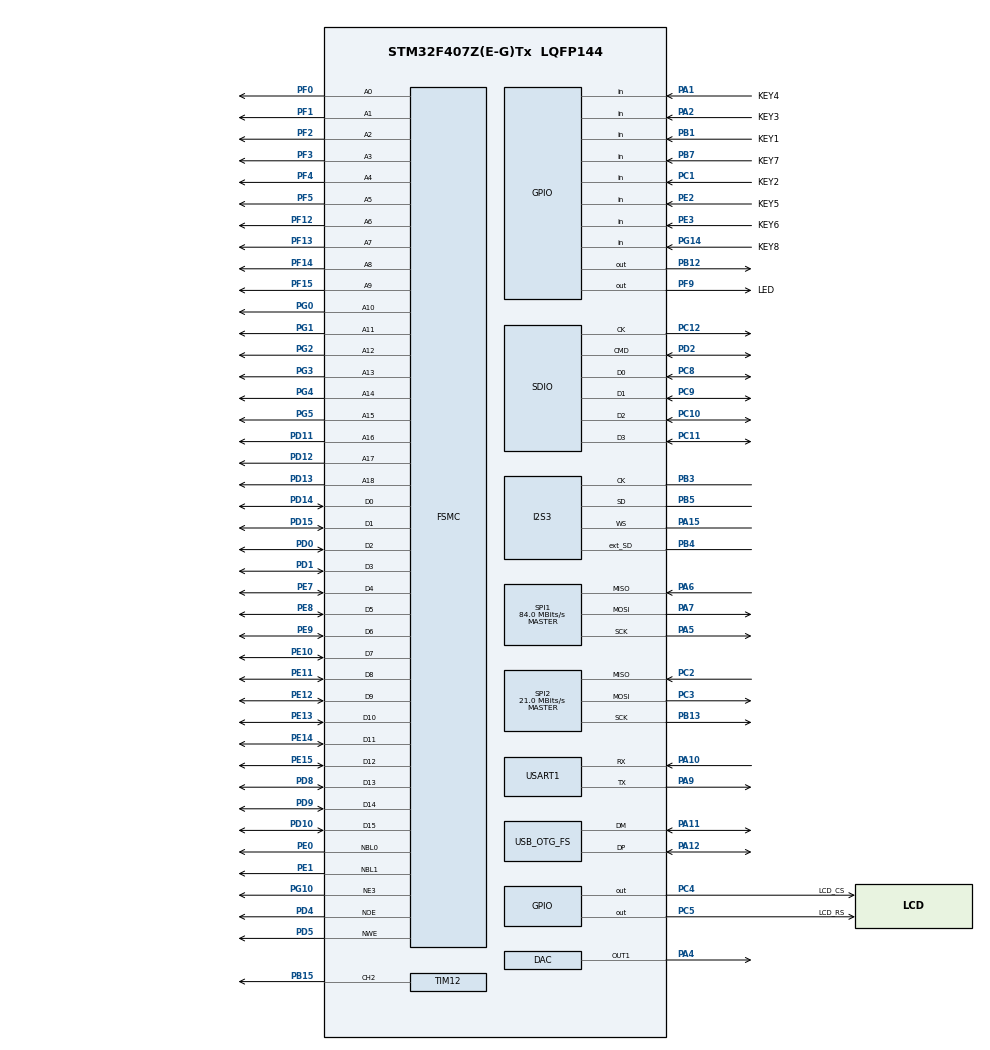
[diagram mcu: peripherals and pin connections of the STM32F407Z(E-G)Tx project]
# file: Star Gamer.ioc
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Dma.Request0=SDIO_RX
Dma.Request1=SDIO_TX
Dma.Request2=SPI2_TX
Dma.Request3=SPI1_TX
Dma.Request4=SPI1_RX
Dma.Request5=SPI3_TX
Dma.SDIO_RX.0.Direction=DMA_PERIPH_TO_MEMORY
Dma.SDIO_RX.0.FIFOMode=DMA_FIFOMODE_ENABLE
Dma.SDIO_RX.0.FIFOThreshold=DMA_FIFO_THRESHOLD_FULL
Dma.SDIO_RX.0.Instance=DMA2_Stream3
Dma.SDIO_RX.0.MemBurst=DMA_MBURST_INC4
Dma.SDIO_RX.0.MemDataAlignment=DMA_MDATAALIGN_WORD
Dma.SDIO_RX.0.MemInc=DMA_MINC_ENABLE
Dma.SDIO_RX.0.Mode=DMA_PFCTRL
Dma.SDIO_RX.0.PeriphBurst=DMA_PBURST_INC4
Dma.SDIO_RX.0.PeriphDataAlignment=DMA_PDATAALIGN_WORD
Dma.SDIO_RX.0.PeriphInc=DMA_PINC_DISABLE
Dma.SDIO_RX.0.Priority=DMA_PRIORITY_VERY_HIGH
Dma.SDIO_TX.1.Direction=DMA_MEMORY_TO_PERIPH
Dma.SDIO_TX.1.FIFOMode=DMA_FIFOMODE_ENABLE
Dma.SDIO_TX.1.FIFOThreshold=DMA_FIFO_THRESHOLD_FULL
Dma.SDIO_TX.1.Instance=DMA2_Stream6
Dma.SDIO_TX.1.MemBurst=DMA_MBURST_INC4
Dma.SDIO_TX.1.MemDataAlignment=DMA_MDATAALIGN_WORD
Dma.SDIO_TX.1.MemInc=DMA_MINC_ENABLE
Dma.SDIO_TX.1.Mode=DMA_PFCTRL
Dma.SDIO_TX.1.PeriphBurst=DMA_PBURST_INC4
Dma.SDIO_TX.1.PeriphDataAlignment=DMA_PDATAALIGN_WORD
Dma.SDIO_TX.1.PeriphInc=DMA_PINC_DISABLE
Dma.SDIO_TX.1.Priority=DMA_PRIORITY_VERY_HIGH
Dma.SPI1_RX.4.Direction=DMA_PERIPH_TO_MEMORY
Dma.SPI1_RX.4.FIFOMode=DMA_FIFOMODE_DISABLE
Dma.SPI1_RX.4.Instance=DMA2_Stream0
Dma.SPI1_RX.4.MemDataAlignment=DMA_MDATAALIGN_BYTE
Dma.SPI1_RX.4.MemInc=DMA_MINC_ENABLE
Dma.SPI1_RX.4.Mode=DMA_NORMAL
Dma.SPI1_RX.4.PeriphDataAlignment=DMA_PDATAALIGN_BYTE
Dma.SPI1_RX.4.PeriphInc=DMA_PINC_DISABLE
Dma.SPI1_RX.4.Priority=DMA_PRIORITY_MEDIUM
Dma.SPI1_TX.3.Direction=DMA_MEMORY_TO_PERIPH
Dma.SPI1_TX.3.FIFOMode=DMA_FIFOMODE_DISABLE
Dma.SPI1_TX.3.Instance=DMA2_Stream5
Dma.SPI1_TX.3.MemDataAlignment=DMA_MDATAALIGN_BYTE
Dma.SPI1_TX.3.MemInc=DMA_MINC_ENABLE
Dma.SPI1_TX.3.Mode=DMA_NORMAL
Dma.SPI1_TX.3.PeriphDataAlignment=DMA_PDATAALIGN_BYTE
Dma.SPI1_TX.3.PeriphInc=DMA_PINC_DISABLE
Dma.SPI1_TX.3.Priority=DMA_PRIORITY_MEDIUM
Dma.SPI2_TX.2.Direction=DMA_MEMORY_TO_PERIPH
Dma.SPI2_TX.2.FIFOMode=DMA_FIFOMODE_DISABLE
Dma.SPI2_TX.2.Instance=DMA1_Stream4
Dma.SPI2_TX.2.MemDataAlignment=DMA_MDATAALIGN_BYTE
Dma.SPI2_TX.2.MemInc=DMA_MINC_ENABLE
Dma.SPI2_TX.2.Mode=DMA_NORMAL
Dma.SPI2_TX.2.PeriphDataAlignment=DMA_PDATAALIGN_BYTE
Dma.SPI2_TX.2.PeriphInc=DMA_PINC_DISABLE
Dma.SPI2_TX.2.Priority=DMA_PRIORITY_LOW
Dma.SPI3_TX.5.Direction=DMA_MEMORY_TO_PERIPH
Dma.SPI3_TX.5.FIFOMode=DMA_FIFOMODE_DISABLE
Dma.SPI3_TX.5.Instance=DMA1_Stream7
Dma.SPI3_TX.5.MemDataAlignment=DMA_MDATAALIGN_HALFWORD
Dma.SPI3_TX.5.MemInc=DMA_MINC_ENABLE
Dma.SPI3_TX.5.Mode=DMA_CIRCULAR
Dma.SPI3_TX.5.PeriphDataAlignment=DMA_PDATAALIGN_HALFWORD
Dma.SPI3_TX.5.PeriphInc=DMA_PINC_DISABLE
Dma.SPI3_TX.5.Priority=DMA_PRIORITY_HIGH
FATFS._CODE_PAGE=936
FATFS._USE_LFN=3
FATFS._USE_MUTEX=1
FREERTOS.INCLUDE_xEventGroupSetBitFromISR=1
FREERTOS.Tasks01=defaultTask,24,1024,StartDefaultTask,Default,NULL,Static,defaultTaskBuffer,defaultTaskControlBlock
FREERTOS.configCHECK_FOR_STACK_OVERFLOW=1
FREERTOS.configTOTAL_HEAP_SIZE=1024
FSMC.AddressSetupTime3=0
FSMC.BusTurnAroundDuration3=0
FSMC.DataSetupTime3=8
FSMC.WriteOperation3=FSMC_WRITE_OPERATION_ENABLE
I2S3.AudioFreq=I2S_AUDIOFREQ_22K
I2S3.DataFormat=I2S_DATAFORMAT_16B
I2S3.ErrorAudioFreq=-0.1 %
I2S3.FullDuplexMode=I2S_FULLDUPLEXMODE_ENABLE
I2S3.Instance=SPI$Index
I2S3.Mode=I2S_MODE_MASTER_TX
I2S3.RealAudioFreq=21.978 KHz
I2S3.VirtualMode=I2S_MODE_MASTER
Mcu.Family=STM32F4
Mcu.Name=STM32F407Z(E-G)Tx
Mcu.Package=LQFP144
NVIC.DMA1_Stream4_IRQn=true\:6\:0\:true\:false\:true\:true\:false\:true\:true
NVIC.DMA1_Stream7_IRQn=true\:5\:0\:false\:false\:true\:true\:false\:true\:true
NVIC.DMA2_Stream0_IRQn=true\:6\:0\:true\:false\:true\:true\:false\:true\:true
NVIC.DMA2_Stream3_IRQn=true\:5\:0\:true\:false\:true\:true\:false\:true\:true
NVIC.DMA2_Stream5_IRQn=true\:6\:0\:true\:false\:true\:true\:false\:true\:true
NVIC.DMA2_Stream6_IRQn=true\:5\:0\:true\:false\:true\:true\:false\:true\:true
NVIC.OTG_FS_IRQn=true\:5\:0\:false\:false\:true\:true\:false\:true\:true
NVIC.PriorityGroup=NVIC_PRIORITYGROUP_4
NVIC.SDIO_IRQn=true\:6\:0\:false\:false\:true\:true\:true\:true\:true
NVIC.SPI2_IRQn=true\:5\:0\:true\:false\:true\:true\:true\:true\:true
NVIC.TIM6_DAC_IRQn=true\:0\:0\:true\:false\:true\:false\:false\:true\:true
NVIC.TimeBase=TIM6_DAC_IRQn
NVIC.TimeBaseIP=TIM6
NVIC.USART1_IRQn=true\:5\:0\:false\:false\:true\:true\:true\:true\:true
PA1.GPIO_Label=KEY4
PA1.GPIO_PuPd=GPIO_PULLUP
PA1.Signal=GPIO_Input
PA10.Mode=Asynchronous
PA10.Signal=USART1_RX
PA11.Mode=Device_Only
PA11.Signal=USB_OTG_FS_DM
PA12.Mode=Device_Only
PA12.Signal=USB_OTG_FS_DP
PA13.Mode=Serial_Wire
PA13.Signal=SYS_JTMS-SWDIO
PA14.Mode=Serial_Wire
PA14.Signal=SYS_JTCK-SWCLK
PA15.Mode=Full_Duplex_Master
PA15.Signal=I2S3_WS
PA2.GPIO_Label=KEY3
PA2.GPIO_PuPd=GPIO_PULLUP
PA2.Signal=GPIO_Input
PA4.Signal=COMP_DAC1_group
PA5.Mode=Full_Duplex_Master
PA5.Signal=SPI1_SCK
PA6.Mode=Full_Duplex_Master
PA6.Signal=SPI1_MISO
PA7.Mode=Full_Duplex_Master
PA7.Signal=SPI1_MOSI
PA9.Mode=Asynchronous
PA9.Signal=USART1_TX
PB1.GPIO_Label=KEY1
PB1.GPIO_PuPd=GPIO_PULLUP
PB1.Signal=GPIO_Input
PB12.Signal=GPIO_Output
PB13.Mode=Full_Duplex_Master
PB13.Signal=SPI2_SCK
PB15.Signal=S_TIM12_CH2
PB3.Mode=Full_Duplex_Master
PB3.Signal=I2S3_CK
PB4.Mode=Full_Duplex_Master
PB4.Signal=I2S3_ext_SD
PB5.Mode=Full_Duplex_Master
PB5.Signal=I2S3_SD
PB7.GPIO_Label=KEY7
PB7.GPIO_PuPd=GPIO_PULLUP
PB7.Signal=GPIO_Input
PB8.Signal=I2C1_SCL
PB9.Signal=I2C1_SDA
PC1.GPIO_Label=KEY2
PC1.GPIO_PuPd=GPIO_PULLUP
PC1.Signal=GPIO_Input
PC10.Mode=SD_4_bits_Wide_bus
PC10.Signal=SDIO_D2
PC11.Mode=SD_4_bits_Wide_bus
PC11.Signal=SDIO_D3
PC12.Mode=SD_4_bits_Wide_bus
PC12.Signal=SDIO_CK
PC2.Mode=Full_Duplex_Master
PC2.Signal=SPI2_MISO
PC3.Mode=Full_Duplex_Master
PC3.Signal=SPI2_MOSI
PC4.GPIO_Label=LCD_CS
PC4.GPIO_Speed=GPIO_SPEED_FREQ_MEDIUM
PC4.Signal=GPIO_Output
PC5.GPIO_Label=LCD_RS
PC5.GPIO_Speed=GPIO_SPEED_FREQ_MEDIUM
PC5.Signal=GPIO_Output
PC8.Mode=SD_4_bits_Wide_bus
PC8.Signal=SDIO_D0
PC9.Mode=SD_4_bits_Wide_bus
PC9.Signal=SDIO_D1
PD0.Signal=FSMC_D2_DA2
PD1.Signal=FSMC_D3_DA3
PD10.Signal=FSMC_D15_DA15
PD11.Signal=FSMC_A16_CLE
PD12.Signal=FSMC_A17_ALE
PD13.Signal=FSMC_A18
PD14.Signal=FSMC_D0_DA0
PD15.Signal=FSMC_D1_DA1
PD2.Mode=SD_4_bits_Wide_bus
PD2.Signal=SDIO_CMD
PD4.Signal=FSMC_NOE
PD5.Signal=FSMC_NWE
PD8.Signal=FSMC_D13_DA13
PD9.Signal=FSMC_D14_DA14
PE0.Signal=FSMC_NBL0
PE1.Signal=FSMC_NBL1
PE10.Signal=FSMC_D7_DA7
PE11.Signal=FSMC_D8_DA8
PE12.Signal=FSMC_D9_DA9
PE13.Signal=FSMC_D10_DA10
PE14.Signal=FSMC_D11_DA11
PE15.Signal=FSMC_D12_DA12
PE2.GPIO_Label=KEY5
PE2.GPIO_PuPd=GPIO_PULLUP
PE2.Signal=GPIO_Input
PE3.GPIO_Label=KEY6
PE3.GPIO_PuPd=GPIO_PULLUP
PE3.Signal=GPIO_Input
PE7.Signal=FSMC_D4_DA4
PE8.Signal=FSMC_D5_DA5
PE9.Signal=FSMC_D6_DA6
PF0.Signal=FSMC_A0
PF1.Signal=FSMC_A1
PF12.Signal=FSMC_A6
PF13.Signal=FSMC_A7
PF14.Signal=FSMC_A8
PF15.Signal=FSMC_A9
PF2.Signal=FSMC_A2
PF3.Signal=FSMC_A3
PF4.Signal=FSMC_A4
PF5.Signal=FSMC_A5
PF9.GPIO_Label=LED
PF9.PinState=GPIO_PIN_SET
PF9.Signal=GPIO_Output
PG0.Signal=FSMC_A10
PG1.Signal=FSMC_A11
PG10.Mode=NorPsramChipSelect3_3
PG10.Signal=FSMC_NE3
PG14.GPIO_Label=KEY8
PG14.GPIO_PuPd=GPIO_PULLUP
PG14.Signal=GPIO_Input
PG2.Signal=FSMC_A12
PG3.Signal=FSMC_A13
PG4.Signal=FSMC_A14
PG5.Signal=FSMC_A15
PH0-OSC_IN.Mode=HSE-External-Oscillator
PH0-OSC_IN.Signal=RCC_OSC_IN
PH1-OSC_OUT.Mode=HSE-External-Oscillator
PH1-OSC_OUT.Signal=RCC_OSC_OUT
ProjectManager.HeapSize=0x400
ProjectManager.StackSize=0x400
ProjectManager.TargetToolchain=MDK-ARM V5.32
RCC.48MHZClocksFreq_Value=48000000
RCC.AHBFreq_Value=168000000
RCC.APB1CLKDivider=RCC_HCLK_DIV4
RCC.APB1Freq_Value=42000000
RCC.APB1TimFreq_Value=84000000
RCC.APB2CLKDivider=RCC_HCLK_DIV1
RCC.APB2Freq_Value=168000000
RCC.APB2TimFreq_Value=168000000
RCC.CortexFreq_Value=168000000
RCC.HCLKFreq_Value=168000000
RCC.HSE_VALUE=8000000
RCC.HSI_VALUE=16000000
RCC.LSE_VALUE=32768
RCC.PLLM=4
RCC.PLLN=168
RCC.PLLQ=7
RCC.SYSCLKFreq_VALUE=168000000
RCC.SYSCLKSource=RCC_SYSCLKSOURCE_PLLCLK
RCC.VCOOutputFreq_Value=336000000
SDIO.ClockDiv=4
SH.COMP_DAC1_group.0=DAC_OUT1,DAC_OUT1
SH.FSMC_A0.0=FSMC_A0,19b-a3
SH.FSMC_A1.0=FSMC_A1,19b-a3
SH.FSMC_A10.0=FSMC_A10,19b-a3
SH.FSMC_A11.0=FSMC_A11,19b-a3
SH.FSMC_A12.0=FSMC_A12,19b-a3
SH.FSMC_A13.0=FSMC_A13,19b-a3
SH.FSMC_A14.0=FSMC_A14,19b-a3
SH.FSMC_A15.0=FSMC_A15,19b-a3
SH.FSMC_A16_CLE.0=FSMC_A16,19b-a3
SH.FSMC_A17_ALE.0=FSMC_A17,19b-a3
SH.FSMC_A18.0=FSMC_A18,19b-a3
SH.FSMC_A2.0=FSMC_A2,19b-a3
SH.FSMC_A3.0=FSMC_A3,19b-a3
SH.FSMC_A4.0=FSMC_A4,19b-a3
SH.FSMC_A5.0=FSMC_A5,19b-a3
SH.FSMC_A6.0=FSMC_A6,19b-a3
SH.FSMC_A7.0=FSMC_A7,19b-a3
SH.FSMC_A8.0=FSMC_A8,19b-a3
SH.FSMC_A9.0=FSMC_A9,19b-a3
SH.FSMC_D0_DA0.0=FSMC_D0,16b-d3
SH.FSMC_D10_DA10.0=FSMC_D10,16b-d3
SH.FSMC_D11_DA11.0=FSMC_D11,16b-d3
SH.FSMC_D12_DA12.0=FSMC_D12,16b-d3
SH.FSMC_D13_DA13.0=FSMC_D13,16b-d3
SH.FSMC_D14_DA14.0=FSMC_D14,16b-d3
SH.FSMC_D15_DA15.0=FSMC_D15,16b-d3
SH.FSMC_D1_DA1.0=FSMC_D1,16b-d3
SH.FSMC_D2_DA2.0=FSMC_D2,16b-d3
SH.FSMC_D3_DA3.0=FSMC_D3,16b-d3
SH.FSMC_D4_DA4.0=FSMC_D4,16b-d3
SH.FSMC_D5_DA5.0=FSMC_D5,16b-d3
SH.FSMC_D6_DA6.0=FSMC_D6,16b-d3
SH.FSMC_D7_DA7.0=FSMC_D7,16b-d3
SH.FSMC_D8_DA8.0=FSMC_D8,16b-d3
SH.FSMC_D9_DA9.0=FSMC_D9,16b-d3
SH.FSMC_NBL0.0=FSMC_NBL0,2ByteEnable3
SH.FSMC_NBL1.0=FSMC_NBL1,2ByteEnable3
SH.FSMC_NOE.0=FSMC_NOE,Sram3
SH.FSMC_NWE.0=FSMC_NWE,Sram3
SH.S_TIM12_CH2.0=TIM12_CH2,PWM Generation2 CH2
SPI1.CalculateBaudRate=84.0 MBits/s
SPI1.Direction=SPI_DIRECTION_2LINES
SPI1.Mode=SPI_MODE_MASTER
SPI1.VirtualType=VM_MASTER
SPI2.CRCCalculation=SPI_CRCCALCULATION_DISABLE
SPI2.CalculateBaudRate=21.0 MBits/s
SPI2.Direction=SPI_DIRECTION_2LINES
SPI2.Mode=SPI_MODE_MASTER
SPI2.VirtualType=VM_MASTER
TIM12.Channel-PWM\ Generation2\ CH2=TIM_CHANNEL_2
TIM7.AutoReloadPreload=TIM_AUTORELOAD_PRELOAD_ENABLE
TIM7.Period=72-1
TIM7.TIM_MasterOutputTrigger=TIM_TRGO_UPDATE
USART1.VirtualMode=VM_ASYNC
USB_DEVICE.CLASS_NAME_FS=MSC
USB_DEVICE.VirtualMode-MSC_FS=Msc
USB_DEVICE.VirtualModeFS=Msc_FS
USB_OTG_FS.VirtualMode=Device_Only
VP_CRC_VS_CRC.Mode=CRC_Activate
VP_FATFS_VS_SDIO.Mode=SDIO
VP_FREERTOS_VS_CMSIS_V2.Mode=CMSIS_V2
VP_LIBJPEG_VS_JPEGLIB.Mode=Enabled
VP_RNG_VS_RNG.Mode=RNG_Activate
VP_SYS_VS_tim6.Mode=TIM6
VP_TIM11_VS_ClockSourceINT.Mode=Enable_Timer
VP_TIM12_VS_ClockSourceINT.Mode=Internal
VP_TIM7_VS_ClockSourceINT.Mode=Enable_Timer
VP_USB_DEVICE_VS_USB_DEVICE_MSC_FS.Mode=MSC_FS
board=custom

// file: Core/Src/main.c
/* USER CODE BEGIN Header */
/**
  ******************************************************************************
  * @file           : main.c
  * @brief          : Main program body
  ******************************************************************************
  * @attention
  *
  * Copyright (c) 2025 STMicroelectronics.
  * All rights reserved.
  *
  * This software is licensed under terms that can be found in the LICENSE file
  * in the root directory of this software component.
  * If no LICENSE file comes with this software, it is provided AS-IS.
  *
  ******************************************************************************
  */
/* USER CODE END Header */
#include "main.h"
#include "cmsis_os.h"
#include "fatfs.h"
#include "libjpeg.h"
#include "usb_device.h"

/* USER CODE BEGIN Includes */
#include "fatfs.h"
#include "ff.h"
#include "stdio.h"
#include "string.h"
#include "Player.h"
#include "System_Status.h"
#include "Malloc.h"
#include "LCD.h"
#include "dl_lib.h"
#include "nes_main.h"
#include "shell.h"
#include "shell_support.h"
#include "firmware.h"
#include "ccm_memory.h"

System_Status_Information_t SSI;
System_Core_Information_t SCI;
System_Resource_Table_t SRT;
System_Settings_t System_Settings;
Shell shell;

extern void System_init(void);
extern void test_run(void);
/* USER CODE END Includes */

typedef StaticTask_t osStaticThreadDef_t;

/* USER CODE BEGIN PD */
#define DEFAULT_TASK_STACK_SIZE 4096U

/* USER CODE END PD */

CRC_HandleTypeDef hcrc;

DAC_HandleTypeDef hdac;

I2S_HandleTypeDef hi2s3;
DMA_HandleTypeDef hdma_spi3_tx;

RNG_HandleTypeDef hrng;

SD_HandleTypeDef hsd;
DMA_HandleTypeDef hdma_sdio_rx;
DMA_HandleTypeDef hdma_sdio_tx;

SPI_HandleTypeDef hspi1;
SPI_HandleTypeDef hspi2;
DMA_HandleTypeDef hdma_spi1_tx;
DMA_HandleTypeDef hdma_spi1_rx;
DMA_HandleTypeDef hdma_spi2_tx;

TIM_HandleTypeDef htim7;
TIM_HandleTypeDef htim11;
TIM_HandleTypeDef htim12;

UART_HandleTypeDef huart1;

SRAM_HandleTypeDef hsram3;

/* Definitions for defaultTask */
osThreadId_t defaultTaskHandle;
uint32_t defaultTaskBuffer[ 1024 ];
osStaticThreadDef_t defaultTaskControlBlock;
const osThreadAttr_t defaultTask_attributes = {
  .name = "defaultTask",
  .cb_mem = &defaultTaskControlBlock,
  .cb_size = sizeof(defaultTaskControlBlock),
  .stack_mem = &defaultTaskBuffer[0],
  .stack_size = sizeof(defaultTaskBuffer),
  .priority = (osPriority_t) osPriorityNormal,
};
/* USER CODE BEGIN PV */
static void *defaultTaskStackMem;
static osThreadAttr_t defaultTaskCcmAttributes;

/* USER CODE END PV */

void SystemClock_Config(void);
static void MX_GPIO_Init(void);
static void MX_DMA_Init(void);
static void MX_FSMC_Init(void);
static void MX_SDIO_SD_Init(void);
static void MX_USART1_UART_Init(void);
static void MX_DAC_Init(void);
static void MX_SPI1_Init(void);
static void MX_SPI2_Init(void);
static void MX_TIM7_Init(void);
static void MX_I2S3_Init(void);
static void MX_RNG_Init(void);
static void MX_TIM11_Init(void);
static void MX_TIM12_Init(void);
static void MX_CRC_Init(void);
void StartDefaultTask(void *argument);

/* USER CODE BEGIN PFP */
void StartDacTestTask(void *argument);
/* USER CODE END PFP */

/* USER CODE BEGIN 0 */
void SystemClock_SwitchToHSI(void)
{
    // 将系统时钟切换到 HSI
    __HAL_RCC_SYSCLK_CONFIG(RCC_SYSCLKSOURCE_HSI);

    // 等待时钟切换完成
    while (__HAL_RCC_GET_SYSCLK_SOURCE() != RCC_SYSCLKSOURCE_STATUS_HSI) {}
}

void SystemClock_SwitchToPLL(void)
{
    // 将系统时钟切换到 PLL
    __HAL_RCC_SYSCLK_CONFIG(RCC_SYSCLKSOURCE_PLLCLK);

    // 等待时钟切换完成
    while (__HAL_RCC_GET_SYSCLK_SOURCE() != RCC_SYSCLKSOURCE_STATUS_PLLCLK) {}
}
/* USER CODE END 0 */

int main(void)
{

  /* USER CODE BEGIN 1 */
  SCB->VTOR = 0x08010000UL;
  __DSB();
  __ISB();
  /* USER CODE END 1 */

  /* MCU Configuration--------------------------------------------------------*/

  /* Reset of all peripherals, Initializes the Flash interface and the Systick. */
  HAL_Init();

  /* USER CODE BEGIN Init */
  /* Load the persisted clock profile before PLL configuration. */
  if (System_Settings_Init() != SYSTEM_STATUS_OK)
  {
    System_Settings_SetDefaults(&System_Settings);
  }
  /* USER CODE END Init */

  /* Configure the system clock */
  SystemClock_Config();

  /* Initialize all configured peripherals */
  MX_GPIO_Init();
  MX_DMA_Init();
  MX_FSMC_Init();
  MX_SDIO_SD_Init();
  MX_FATFS_Init();
  MX_USART1_UART_Init();
  MX_DAC_Init();
  MX_SPI1_Init();
  MX_SPI2_Init();
  MX_TIM7_Init();
  MX_LIBJPEG_Init();
  MX_I2S3_Init();
  MX_RNG_Init();
  MX_TIM11_Init();
  MX_TIM12_Init();
  MX_CRC_Init();

  /* Init scheduler */
  osKernelInitialize();

  /* USER CODE BEGIN RTOS_MUTEX */
  sys_mem_init(SRAMCCM);
  defaultTaskStackMem = sys_thread_stack_alloc(DEFAULT_TASK_STACK_SIZE);
  if (defaultTaskStackMem == NULL)
  {
    Error_Handler();
  }
  defaultTaskCcmAttributes = defaultTask_attributes;
  defaultTaskCcmAttributes.stack_mem = defaultTaskStackMem;
  defaultTaskCcmAttributes.stack_size = DEFAULT_TASK_STACK_SIZE;
#define defaultTask_attributes defaultTaskCcmAttributes
  /* add mutexes, ... */
  /* USER CODE END RTOS_MUTEX */

  /* Create the thread(s) */
  /* creation of defaultTask */
  defaultTaskHandle = osThreadNew(StartDefaultTask, NULL, &defaultTask_attributes);

  /* Start scheduler */
  osKernelStart();

  /* We should never get here as control is now taken by the scheduler */

  /* Infinite loop */
  while (1)
  {

  }
}

void SystemClock_Config(void)
{
  RCC_OscInitTypeDef RCC_OscInitStruct = {0};
  RCC_ClkInitTypeDef RCC_ClkInitStruct = {0};

  /** Configure the main internal regulator output voltage
  */
  __HAL_RCC_PWR_CLK_ENABLE();
  __HAL_PWR_VOLTAGESCALING_CONFIG(PWR_REGULATOR_VOLTAGE_SCALE1);
	SystemClock_SwitchToHSI();

  /** Initializes the RCC Oscillators according to the specified parameters
  * in the RCC_OscInitTypeDef structure.
  */
  RCC_OscInitStruct.OscillatorType = RCC_OSCILLATORTYPE_HSE;
  RCC_OscInitStruct.HSEState = RCC_HSE_ON;
  RCC_OscInitStruct.PLL.PLLState = RCC_PLL_ON;
  RCC_OscInitStruct.PLL.PLLSource = RCC_PLLSOURCE_HSE;
  RCC_OscInitStruct.PLL.PLLM = 4;
  /* USER CODE BEGIN ClockPll */
  RCC_OscInitStruct.PLL.PLLN = System_Settings_ClockPllN();
  RCC_OscInitStruct.PLL.PLLP = RCC_PLLP_DIV2;
  RCC_OscInitStruct.PLL.PLLQ = 5;
  /* USER CODE END ClockPll */
  if (HAL_RCC_OscConfig(&RCC_OscInitStruct) != HAL_OK)
  {
    Error_Handler();
  }

  /** Initializes the CPU, AHB and APB buses clocks
  */
  RCC_ClkInitStruct.ClockType = RCC_CLOCKTYPE_HCLK|RCC_CLOCKTYPE_SYSCLK
                              |RCC_CLOCKTYPE_PCLK1|RCC_CLOCKTYPE_PCLK2;
  RCC_ClkInitStruct.SYSCLKSource = RCC_SYSCLKSOURCE_PLLCLK;
  RCC_ClkInitStruct.AHBCLKDivider = RCC_SYSCLK_DIV1;
  RCC_ClkInitStruct.APB1CLKDivider = RCC_HCLK_DIV4;
  RCC_ClkInitStruct.APB2CLKDivider = RCC_HCLK_DIV2;

  if (HAL_RCC_ClockConfig(&RCC_ClkInitStruct, FLASH_LATENCY_7) != HAL_OK)
  {
    Error_Handler();
  }

	SystemClock_SwitchToPLL();
}

static void MX_CRC_Init(void)
{

  hcrc.Instance = CRC;
  if (HAL_CRC_Init(&hcrc) != HAL_OK)
  {
    Error_Handler();
  }

}

static void MX_DAC_Init(void)
{

  DAC_ChannelConfTypeDef sConfig = {0};

  /** DAC Initialization
  */
  hdac.Instance = DAC;
  if (HAL_DAC_Init(&hdac) != HAL_OK)
  {
    Error_Handler();
  }

  /** DAC channel OUT1 config
  */
  sConfig.DAC_Trigger = DAC_TRIGGER_NONE;
  sConfig.DAC_OutputBuffer = DAC_OUTPUTBUFFER_ENABLE;
  if (HAL_DAC_ConfigChannel(&hdac, &sConfig, DAC_CHANNEL_1) != HAL_OK)
  {
    Error_Handler();
  }

}

static void MX_I2S3_Init(void)
{

  hi2s3.Instance = SPI3;
  hi2s3.Init.Mode = I2S_MODE_MASTER_TX;
  hi2s3.Init.Standard = I2S_STANDARD_PHILIPS;
  hi2s3.Init.DataFormat = I2S_DATAFORMAT_16B;
  hi2s3.Init.MCLKOutput = I2S_MCLKOUTPUT_DISABLE;
  hi2s3.Init.AudioFreq = I2S_AUDIOFREQ_22K;
  hi2s3.Init.CPOL = I2S_CPOL_LOW;
  hi2s3.Init.ClockSource = I2S_CLOCK_PLL;
  hi2s3.Init.FullDuplexMode = I2S_FULLDUPLEXMODE_ENABLE;
  if (HAL_I2S_Init(&hi2s3) != HAL_OK)
  {
    Error_Handler();
  }

}

static void MX_RNG_Init(void)
{

  hrng.Instance = RNG;
  if (HAL_RNG_Init(&hrng) != HAL_OK)
  {
    Error_Handler();
  }

}

static void MX_SDIO_SD_Init(void)
{

  hsd.Instance = SDIO;
  hsd.Init.ClockEdge = SDIO_CLOCK_EDGE_RISING;
  hsd.Init.ClockBypass = SDIO_CLOCK_BYPASS_DISABLE;
  hsd.Init.ClockPowerSave = SDIO_CLOCK_POWER_SAVE_DISABLE;
  hsd.Init.BusWide = SDIO_BUS_WIDE_1B;
  hsd.Init.HardwareFlowControl = SDIO_HARDWARE_FLOW_CONTROL_DISABLE;
  hsd.Init.ClockDiv = 0;

}

static void MX_SPI1_Init(void)
{

  /* SPI1 parameter configuration*/
  hspi1.Instance = SPI1;
  hspi1.Init.Mode = SPI_MODE_MASTER;
  hspi1.Init.Direction = SPI_DIRECTION_2LINES;
  hspi1.Init.DataSize = SPI_DATASIZE_8BIT;
  hspi1.Init.CLKPolarity = SPI_POLARITY_LOW;
  hspi1.Init.CLKPhase = SPI_PHASE_1EDGE;
  hspi1.Init.NSS = SPI_NSS_SOFT;
  hspi1.Init.BaudRatePrescaler = SPI_BAUDRATEPRESCALER_2;
  hspi1.Init.FirstBit = SPI_FIRSTBIT_MSB;
  hspi1.Init.TIMode = SPI_TIMODE_DISABLE;
  hspi1.Init.CRCCalculation = SPI_CRCCALCULATION_DISABLE;
  hspi1.Init.CRCPolynomial = 10;
  if (HAL_SPI_Init(&hspi1) != HAL_OK)
  {
    Error_Handler();
  }

}

static void MX_SPI2_Init(void)
{

  /* SPI2 parameter configuration*/
  hspi2.Instance = SPI2;
  hspi2.Init.Mode = SPI_MODE_MASTER;
  hspi2.Init.Direction = SPI_DIRECTION_2LINES;
  hspi2.Init.DataSize = SPI_DATASIZE_8BIT;
  hspi2.Init.CLKPolarity = SPI_POLARITY_LOW;
  hspi2.Init.CLKPhase = SPI_PHASE_1EDGE;
  hspi2.Init.NSS = SPI_NSS_SOFT;
  hspi2.Init.BaudRatePrescaler = SPI_BAUDRATEPRESCALER_2;
  hspi2.Init.FirstBit = SPI_FIRSTBIT_MSB;
  hspi2.Init.TIMode = SPI_TIMODE_DISABLE;
  hspi2.Init.CRCCalculation = SPI_CRCCALCULATION_DISABLE;
  hspi2.Init.CRCPolynomial = 10;
  if (HAL_SPI_Init(&hspi2) != HAL_OK)
  {
    Error_Handler();
  }

}

static void MX_TIM7_Init(void)
{

  TIM_MasterConfigTypeDef sMasterConfig = {0};

  htim7.Instance = TIM7;
  htim7.Init.Prescaler = 0;
  htim7.Init.CounterMode = TIM_COUNTERMODE_UP;
  htim7.Init.Period = 72-1;
  htim7.Init.AutoReloadPreload = TIM_AUTORELOAD_PRELOAD_ENABLE;
  if (HAL_TIM_Base_Init(&htim7) != HAL_OK)
  {
    Error_Handler();
  }
  sMasterConfig.MasterOutputTrigger = TIM_TRGO_UPDATE;
  sMasterConfig.MasterSlaveMode = TIM_MASTERSLAVEMODE_DISABLE;
  if (HAL_TIMEx_MasterConfigSynchronization(&htim7, &sMasterConfig) != HAL_OK)
  {
    Error_Handler();
  }

}

static void MX_TIM11_Init(void)
{

  htim11.Instance = TIM11;
  htim11.Init.Prescaler = 0;
  htim11.Init.CounterMode = TIM_COUNTERMODE_UP;
  htim11.Init.Period = 65535;
  htim11.Init.ClockDivision = TIM_CLOCKDIVISION_DIV1;
  htim11.Init.AutoReloadPreload = TIM_AUTORELOAD_PRELOAD_DISABLE;
  if (HAL_TIM_Base_Init(&htim11) != HAL_OK)
  {
    Error_Handler();
  }

}

static void MX_TIM12_Init(void)
{

  TIM_ClockConfigTypeDef sClockSourceConfig = {0};
  TIM_OC_InitTypeDef sConfigOC = {0};

  htim12.Instance = TIM12;
  htim12.Init.Prescaler = 0;
  htim12.Init.CounterMode = TIM_COUNTERMODE_UP;
  htim12.Init.Period = 65535;
  htim12.Init.ClockDivision = TIM_CLOCKDIVISION_DIV1;
  htim12.Init.AutoReloadPreload = TIM_AUTORELOAD_PRELOAD_DISABLE;
  if (HAL_TIM_Base_Init(&htim12) != HAL_OK)
  {
    Error_Handler();
  }
  sClockSourceConfig.ClockSource = TIM_CLOCKSOURCE_INTERNAL;
  if (HAL_TIM_ConfigClockSource(&htim12, &sClockSourceConfig) != HAL_OK)
  {
    Error_Handler();
  }
  if (HAL_TIM_PWM_Init(&htim12) != HAL_OK)
  {
    Error_Handler();
  }
  sConfigOC.OCMode = TIM_OCMODE_PWM1;
  sConfigOC.Pulse = 0;
  sConfigOC.OCPolarity = TIM_OCPOLARITY_HIGH;
  sConfigOC.OCFastMode = TIM_OCFAST_DISABLE;
  if (HAL_TIM_PWM_ConfigChannel(&htim12, &sConfigOC, TIM_CHANNEL_2) != HAL_OK)
  {
    Error_Handler();
  }
  HAL_TIM_MspPostInit(&htim12);

}

static void MX_USART1_UART_Init(void)
{

  huart1.Instance = USART1;
  huart1.Init.BaudRate = 115200;
  huart1.Init.WordLength = UART_WORDLENGTH_8B;
  huart1.Init.StopBits = UART_STOPBITS_1;
  huart1.Init.Parity = UART_PARITY_NONE;
  huart1.Init.Mode = UART_MODE_TX_RX;
  huart1.Init.HwFlowCtl = UART_HWCONTROL_NONE;
  huart1.Init.OverSampling = UART_OVERSAMPLING_16;
  if (HAL_UART_Init(&huart1) != HAL_OK)
  {
    Error_Handler();
  }

}

static void MX_DMA_Init(void)
{

  /* DMA controller clock enable */
  __HAL_RCC_DMA2_CLK_ENABLE();
  __HAL_RCC_DMA1_CLK_ENABLE();

  /* DMA interrupt init */
  /* DMA1_Stream4_IRQn interrupt configuration */
  HAL_NVIC_SetPriority(DMA1_Stream4_IRQn, 6, 0);
  HAL_NVIC_EnableIRQ(DMA1_Stream4_IRQn);
  /* DMA1_Stream7_IRQn interrupt configuration */
  HAL_NVIC_SetPriority(DMA1_Stream7_IRQn, 5, 0);
  HAL_NVIC_EnableIRQ(DMA1_Stream7_IRQn);
  /* DMA2_Stream0_IRQn interrupt configuration */
  HAL_NVIC_SetPriority(DMA2_Stream0_IRQn, 6, 0);
  HAL_NVIC_EnableIRQ(DMA2_Stream0_IRQn);
  /* DMA2_Stream3_IRQn interrupt configuration */
  HAL_NVIC_SetPriority(DMA2_Stream3_IRQn, 5, 0);
  HAL_NVIC_EnableIRQ(DMA2_Stream3_IRQn);
  /* DMA2_Stream5_IRQn interrupt configuration */
  HAL_NVIC_SetPriority(DMA2_Stream5_IRQn, 6, 0);
  HAL_NVIC_EnableIRQ(DMA2_Stream5_IRQn);
  /* DMA2_Stream6_IRQn interrupt configuration */
  HAL_NVIC_SetPriority(DMA2_Stream6_IRQn, 5, 0);
  HAL_NVIC_EnableIRQ(DMA2_Stream6_IRQn);

}

static void MX_GPIO_Init(void)
{
  GPIO_InitTypeDef GPIO_InitStruct = {0};

  /* GPIO Ports Clock Enable */
  __HAL_RCC_GPIOE_CLK_ENABLE();
  __HAL_RCC_GPIOF_CLK_ENABLE();
  __HAL_RCC_GPIOH_CLK_ENABLE();
  __HAL_RCC_GPIOC_CLK_ENABLE();
  __HAL_RCC_GPIOA_CLK_ENABLE();
  __HAL_RCC_GPIOB_CLK_ENABLE();
  __HAL_RCC_GPIOG_CLK_ENABLE();
  __HAL_RCC_GPIOD_CLK_ENABLE();

  /*Configure GPIO pin Output Level */
  HAL_GPIO_WritePin(LED_GPIO_Port, LED_Pin, GPIO_PIN_SET);

  /*Configure GPIO pin Output Level */
  HAL_GPIO_WritePin(GPIOC, LCD_CS_Pin|LCD_RS_Pin, GPIO_PIN_RESET);

  /*Configure GPIO pin Output Level */
  HAL_GPIO_WritePin(GPIOB, GPIO_PIN_12, GPIO_PIN_RESET);

  /*Configure GPIO pins : KEY5_Pin KEY6_Pin */
  GPIO_InitStruct.Pin = KEY5_Pin|KEY6_Pin;
  GPIO_InitStruct.Mode = GPIO_MODE_INPUT;
  GPIO_InitStruct.Pull = GPIO_PULLUP;
  HAL_GPIO_Init(GPIOE, &GPIO_InitStruct);

  /*Configure GPIO pin : LED_Pin */
  GPIO_InitStruct.Pin = LED_Pin;
  GPIO_InitStruct.Mode = GPIO_MODE_OUTPUT_PP;
  GPIO_InitStruct.Pull = GPIO_NOPULL;
  GPIO_InitStruct.Speed = GPIO_SPEED_FREQ_LOW;
  HAL_GPIO_Init(LED_GPIO_Port, &GPIO_InitStruct);

  /*Configure GPIO pin : KEY2_Pin */
  GPIO_InitStruct.Pin = KEY2_Pin;
  GPIO_InitStruct.Mode = GPIO_MODE_INPUT;
  GPIO_InitStruct.Pull = GPIO_PULLUP;
  HAL_GPIO_Init(KEY2_GPIO_Port, &GPIO_InitStruct);

  /*Configure GPIO pins : KEY4_Pin KEY3_Pin */
  GPIO_InitStruct.Pin = KEY4_Pin|KEY3_Pin;
  GPIO_InitStruct.Mode = GPIO_MODE_INPUT;
  GPIO_InitStruct.Pull = GPIO_PULLUP;
  HAL_GPIO_Init(GPIOA, &GPIO_InitStruct);

  /*Configure GPIO pins : LCD_CS_Pin LCD_RS_Pin */
  GPIO_InitStruct.Pin = LCD_CS_Pin|LCD_RS_Pin;
  GPIO_InitStruct.Mode = GPIO_MODE_OUTPUT_PP;
  GPIO_InitStruct.Pull = GPIO_NOPULL;
  GPIO_InitStruct.Speed = GPIO_SPEED_FREQ_MEDIUM;
  HAL_GPIO_Init(GPIOC, &GPIO_InitStruct);

  /*Configure GPIO pins : KEY1_Pin KEY7_Pin */
  GPIO_InitStruct.Pin = KEY1_Pin|KEY7_Pin;
  GPIO_InitStruct.Mode = GPIO_MODE_INPUT;
  GPIO_InitStruct.Pull = GPIO_PULLUP;
  HAL_GPIO_Init(GPIOB, &GPIO_InitStruct);

  /*Configure GPIO pin : PB12 */
  GPIO_InitStruct.Pin = GPIO_PIN_12;
  GPIO_InitStruct.Mode = GPIO_MODE_OUTPUT_PP;
  GPIO_InitStruct.Pull = GPIO_NOPULL;
  GPIO_InitStruct.Speed = GPIO_SPEED_FREQ_LOW;
  HAL_GPIO_Init(GPIOB, &GPIO_InitStruct);

  /*Configure GPIO pin : KEY8_Pin */
  GPIO_InitStruct.Pin = KEY8_Pin;
  GPIO_InitStruct.Mode = GPIO_MODE_INPUT;
  GPIO_InitStruct.Pull = GPIO_PULLUP;
  HAL_GPIO_Init(KEY8_GPIO_Port, &GPIO_InitStruct);

  /*Configure GPIO pins : PB8 PB9 */
  GPIO_InitStruct.Pin = GPIO_PIN_8|GPIO_PIN_9;
  GPIO_InitStruct.Mode = GPIO_MODE_AF_OD;
  GPIO_InitStruct.Pull = GPIO_NOPULL;
  GPIO_InitStruct.Speed = GPIO_SPEED_FREQ_VERY_HIGH;
  GPIO_InitStruct.Alternate = GPIO_AF4_I2C1;
  HAL_GPIO_Init(GPIOB, &GPIO_InitStruct);

}

/* FSMC initialization function */
static void MX_FSMC_Init(void)
{

  FSMC_NORSRAM_TimingTypeDef Timing = {0};

  /** Perform the SRAM3 memory initialization sequence
  */
  hsram3.Instance = FSMC_NORSRAM_DEVICE;
  hsram3.Extended = FSMC_NORSRAM_EXTENDED_DEVICE;
  /* hsram3.Init */
  hsram3.Init.NSBank = FSMC_NORSRAM_BANK3;
  hsram3.Init.DataAddressMux = FSMC_DATA_ADDRESS_MUX_DISABLE;
  hsram3.Init.MemoryType = FSMC_MEMORY_TYPE_SRAM;
  hsram3.Init.MemoryDataWidth = FSMC_NORSRAM_MEM_BUS_WIDTH_16;
  hsram3.Init.BurstAccessMode = FSMC_BURST_ACCESS_MODE_DISABLE;
  hsram3.Init.WaitSignalPolarity = FSMC_WAIT_SIGNAL_POLARITY_LOW;
  hsram3.Init.WrapMode = FSMC_WRAP_MODE_DISABLE;
  hsram3.Init.WaitSignalActive = FSMC_WAIT_TIMING_BEFORE_WS;
  hsram3.Init.WriteOperation = FSMC_WRITE_OPERATION_ENABLE;
  hsram3.Init.WaitSignal = FSMC_WAIT_SIGNAL_DISABLE;
  hsram3.Init.ExtendedMode = FSMC_EXTENDED_MODE_DISABLE;
  hsram3.Init.AsynchronousWait = FSMC_ASYNCHRONOUS_WAIT_DISABLE;
  hsram3.Init.WriteBurst = FSMC_WRITE_BURST_DISABLE;
  hsram3.Init.PageSize = FSMC_PAGE_SIZE_NONE;
  /* Timing */
  Timing.AddressSetupTime = 0;
  Timing.AddressHoldTime = 15;
  Timing.DataSetupTime = 8;
  Timing.BusTurnAroundDuration = 0;
  Timing.CLKDivision = 16;
  Timing.DataLatency = 17;
  Timing.AccessMode = FSMC_ACCESS_MODE_A;
  /* ExtTiming */

  if (HAL_SRAM_Init(&hsram3, &Timing, NULL) != HAL_OK)
  {
    Error_Handler( );
  }

}

void StartDefaultTask(void *argument)
{
  /* init code for USB_DEVICE */
  MX_USB_DEVICE_Init();
  /* USER CODE BEGIN 5 */
	init();
  /* USER CODE END 5 */
}

void HAL_TIM_PeriodElapsedCallback(TIM_HandleTypeDef *htim)
{
  if (htim->Instance == TIM6)
  {
    HAL_IncTick();
  }
}

void Error_Handler(void)
{
  __disable_irq();
  while (1)
  {
  }
}
#ifdef USE_FULL_ASSERT
/**
  * @brief  Reports the name of the source file and the source line number
  *         where the assert_param error has occurred.
  * @param  file: pointer to the source file name
  * @param  line: assert_param error line source number
  * @retval None
  */
void assert_failed(uint8_t *file, uint32_t line)
{
  /* USER CODE BEGIN 6 */
  /* User can add his own implementation to report the file name and line number,
     ex: shellPrintEndLine("Wrong parameters value: file %s on line %d\r\n", file, line) */
  /* USER CODE END 6 */
}
#endif /* USE_FULL_ASSERT */

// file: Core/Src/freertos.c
/* USER CODE BEGIN Header */
/**
  ******************************************************************************
  * File Name          : freertos.c
  * Description        : Code for freertos applications
  ******************************************************************************
  * @attention
  *
  * Copyright (c) 2025 STMicroelectronics.
  * All rights reserved.
  *
  * This software is licensed under terms that can be found in the LICENSE file
  * in the root directory of this software component.
  * If no LICENSE file comes with this software, it is provided AS-IS.
  *
  ******************************************************************************
  */
/* USER CODE END Header */

#include "FreeRTOS.h"
#include "task.h"
#include "main.h"

/* USER CODE BEGIN Includes */
#include "Malloc.h"

/* USER CODE END Includes */

/* USER CODE BEGIN Variables */
static StaticTask_t idleTaskControlBlock;
static StackType_t *idleTaskStack;
static StaticTask_t timerTaskControlBlock;
static StackType_t *timerTaskStack;

/* USER CODE END Variables */

/* Hook prototypes */
void vApplicationStackOverflowHook(xTaskHandle xTask, signed char *pcTaskName);

/* USER CODE BEGIN 4 */
xTaskHandle volatile g_stack_overflow_task;
signed char * volatile g_stack_overflow_task_name;

void vApplicationStackOverflowHook(xTaskHandle xTask, signed char *pcTaskName)
{
   g_stack_overflow_task = xTask;
   g_stack_overflow_task_name = pcTaskName;
   __DMB();
   taskDISABLE_INTERRUPTS();
   for (;;)
   {
      __NOP();
   }
}

void vApplicationGetIdleTaskMemory(StaticTask_t **ppxIdleTaskTCBBuffer,
                                   StackType_t **ppxIdleTaskStackBuffer,
                                   uint32_t *pulIdleTaskStackSize)
{
   if (idleTaskStack == NULL)
   {
      idleTaskStack = (StackType_t *)sys_thread_stack_alloc((u32)configMINIMAL_STACK_SIZE * sizeof(StackType_t));
      configASSERT(idleTaskStack != NULL);
   }

   *ppxIdleTaskTCBBuffer = &idleTaskControlBlock;
   *ppxIdleTaskStackBuffer = idleTaskStack;
   *pulIdleTaskStackSize = (uint32_t)configMINIMAL_STACK_SIZE;
}

void vApplicationGetTimerTaskMemory(StaticTask_t **ppxTimerTaskTCBBuffer,
                                    StackType_t **ppxTimerTaskStackBuffer,
                                    uint32_t *pulTimerTaskStackSize)
{
   if (timerTaskStack == NULL)
   {
      timerTaskStack = (StackType_t *)sys_thread_stack_alloc((u32)configTIMER_TASK_STACK_DEPTH * sizeof(StackType_t));
      configASSERT(timerTaskStack != NULL);
   }

   *ppxTimerTaskTCBBuffer = &timerTaskControlBlock;
   *ppxTimerTaskStackBuffer = timerTaskStack;
   *pulTimerTaskStackSize = (uint32_t)configTIMER_TASK_STACK_DEPTH;
}
/* USER CODE END 4 */
